VERSION 5.8 ;
BUSBITCHARS "[]" ;
DIVIDERCHAR "/" ;
UNITS
    DATABASE MICRONS 2000 ;
END UNITS

VIA PLL_RING_DCO_PHYS_via1_2_2240_1200_1_2_1040_1040
  VIARULE Via1_GEN_HH ;
  CUTSIZE 0.26 0.26 ;
  LAYERS Metal1 Via1 Metal2 ;
  CUTSPACING 0.26 0.26 ;
  ENCLOSURE 0.06 0.17 0.01 0.06 ;
  ROWCOL 1 2 ;
END PLL_RING_DCO_PHYS_via1_2_2240_1200_1_2_1040_1040

VIA PLL_RING_DCO_PHYS_via2_3_2240_1200_1_2_1040_1040
  VIARULE Via2_GEN_HH ;
  CUTSIZE 0.26 0.26 ;
  LAYERS Metal2 Via2 Metal3 ;
  CUTSPACING 0.26 0.26 ;
  ENCLOSURE 0.01 0.06 0.06 0.01 ;
  ROWCOL 1 2 ;
END PLL_RING_DCO_PHYS_via2_3_2240_1200_1_2_1040_1040

VIA PLL_RING_DCO_PHYS_via3_4_2240_1200_1_2_1040_1040
  VIARULE Via3_GEN_HH ;
  CUTSIZE 0.26 0.26 ;
  LAYERS Metal3 Via3 Metal4 ;
  CUTSPACING 0.26 0.26 ;
  ENCLOSURE 0.06 0.01 0.17 0.06 ;
  ROWCOL 1 2 ;
END PLL_RING_DCO_PHYS_via3_4_2240_1200_1_2_1040_1040

VIA PLL_RING_DCO_PHYS_via4_5_2240_1800_2_2_1040_1040
  VIARULE Via4_GEN_HH ;
  CUTSIZE 0.26 0.26 ;
  LAYERS Metal4 Via4 Metal5 ;
  CUTSPACING 0.26 0.26 ;
  ENCLOSURE 0.17 0.06 0.06 0.06 ;
  ROWCOL 2 2 ;
END PLL_RING_DCO_PHYS_via4_5_2240_1800_2_2_1040_1040

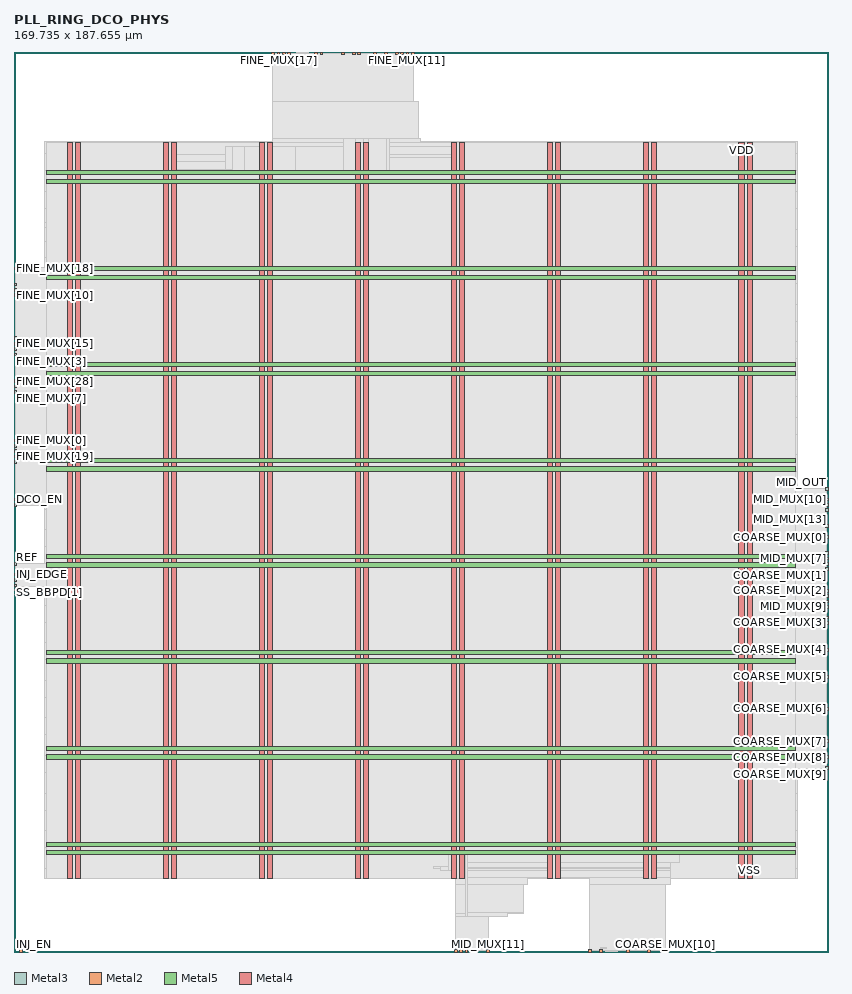
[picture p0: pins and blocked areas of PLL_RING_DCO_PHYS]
MACRO PLL_RING_DCO_PHYS
  FOREIGN PLL_RING_DCO_PHYS 0 0 ;
  CLASS BLOCK ;
  SIZE 169.735 BY 187.655 ;
  PIN COARSE_MUX[0]
    DIRECTION INPUT ;
    USE SIGNAL ;
    PORT
      LAYER Metal3 ;
        RECT  169.175 86.24 169.735 86.8 ;
    END
  END COARSE_MUX[0]
  PIN COARSE_MUX[10]
    DIRECTION INPUT ;
    USE SIGNAL ;
    PORT
      LAYER Metal2 ;
        RECT  135.52 0 136.08 0.56 ;
    END
  END COARSE_MUX[10]
  PIN COARSE_MUX[11]
    DIRECTION INPUT ;
    USE SIGNAL ;
    PORT
      LAYER Metal2 ;
        RECT  132.16 0 132.72 0.56 ;
    END
  END COARSE_MUX[11]
  PIN COARSE_MUX[12]
    DIRECTION INPUT ;
    USE SIGNAL ;
    PORT
      LAYER Metal2 ;
        RECT  127.68 0 128.24 0.56 ;
    END
  END COARSE_MUX[12]
  PIN COARSE_MUX[13]
    DIRECTION INPUT ;
    USE SIGNAL ;
    PORT
      LAYER Metal2 ;
        RECT  122.08 0 122.64 0.56 ;
    END
  END COARSE_MUX[13]
  PIN COARSE_MUX[14]
    DIRECTION INPUT ;
    USE SIGNAL ;
    PORT
      LAYER Metal2 ;
        RECT  119.84 0 120.4 0.56 ;
    END
  END COARSE_MUX[14]
  PIN COARSE_MUX[1]
    DIRECTION INPUT ;
    USE SIGNAL ;
    PORT
      LAYER Metal3 ;
        RECT  169.175 79.52 169.735 80.08 ;
    END
  END COARSE_MUX[1]
  PIN COARSE_MUX[2]
    DIRECTION INPUT ;
    USE SIGNAL ;
    PORT
      LAYER Metal3 ;
        RECT  169.175 75.04 169.735 75.6 ;
    END
  END COARSE_MUX[2]
  PIN COARSE_MUX[3]
    DIRECTION INPUT ;
    USE SIGNAL ;
    PORT
      LAYER Metal3 ;
        RECT  169.175 68.32 169.735 68.88 ;
    END
  END COARSE_MUX[3]
  PIN COARSE_MUX[4]
    DIRECTION INPUT ;
    USE SIGNAL ;
    PORT
      LAYER Metal3 ;
        RECT  169.175 62.72 169.735 63.28 ;
    END
  END COARSE_MUX[4]
  PIN COARSE_MUX[5]
    DIRECTION INPUT ;
    USE SIGNAL ;
    PORT
      LAYER Metal3 ;
        RECT  169.175 57.12 169.735 57.68 ;
    END
  END COARSE_MUX[5]
  PIN COARSE_MUX[6]
    DIRECTION INPUT ;
    USE SIGNAL ;
    PORT
      LAYER Metal3 ;
        RECT  169.175 50.4 169.735 50.96 ;
    END
  END COARSE_MUX[6]
  PIN COARSE_MUX[7]
    DIRECTION INPUT ;
    USE SIGNAL ;
    PORT
      LAYER Metal3 ;
        RECT  169.175 43.68 169.735 44.24 ;
    END
  END COARSE_MUX[7]
  PIN COARSE_MUX[8]
    DIRECTION INPUT ;
    USE SIGNAL ;
    PORT
      LAYER Metal3 ;
        RECT  169.175 40.32 169.735 40.88 ;
    END
  END COARSE_MUX[8]
  PIN COARSE_MUX[9]
    DIRECTION INPUT ;
    USE SIGNAL ;
    PORT
      LAYER Metal3 ;
        RECT  169.175 38.08 169.735 38.64 ;
    END
  END COARSE_MUX[9]
  PIN DCO_EN
    DIRECTION INPUT ;
    USE SIGNAL ;
    PORT
      LAYER Metal3 ;
        RECT  0 94.08 0.56 94.64 ;
    END
  END DCO_EN
  PIN FINE_MUX[0]
    DIRECTION INPUT ;
    USE SIGNAL ;
    PORT
      LAYER Metal3 ;
        RECT  0 106.4 0.56 106.96 ;
    END
  END FINE_MUX[0]
  PIN FINE_MUX[10]
    DIRECTION INPUT ;
    USE SIGNAL ;
    PORT
      LAYER Metal3 ;
        RECT  0 136.64 0.56 137.2 ;
    END
  END FINE_MUX[10]
  PIN FINE_MUX[11]
    DIRECTION INPUT ;
    USE SIGNAL ;
    PORT
      LAYER Metal2 ;
        RECT  81.76 187.095 82.32 187.655 ;
    END
  END FINE_MUX[11]
  PIN FINE_MUX[12]
    DIRECTION INPUT ;
    USE SIGNAL ;
    PORT
      LAYER Metal2 ;
        RECT  71.68 187.095 72.24 187.655 ;
    END
  END FINE_MUX[12]
  PIN FINE_MUX[13]
    DIRECTION INPUT ;
    USE SIGNAL ;
    PORT
      LAYER Metal2 ;
        RECT  68.32 187.095 68.88 187.655 ;
    END
  END FINE_MUX[13]
  PIN FINE_MUX[14]
    DIRECTION INPUT ;
    USE SIGNAL ;
    PORT
      LAYER Metal2 ;
        RECT  77.28 187.095 77.84 187.655 ;
    END
  END FINE_MUX[14]
  PIN FINE_MUX[15]
    DIRECTION INPUT ;
    USE SIGNAL ;
    PORT
      LAYER Metal3 ;
        RECT  0 126.56 0.56 127.12 ;
    END
  END FINE_MUX[15]
  PIN FINE_MUX[16]
    DIRECTION INPUT ;
    USE SIGNAL ;
    PORT
      LAYER Metal2 ;
        RECT  79.52 187.095 80.08 187.655 ;
    END
  END FINE_MUX[16]
  PIN FINE_MUX[17]
    DIRECTION INPUT ;
    USE SIGNAL ;
    PORT
      LAYER Metal2 ;
        RECT  54.88 187.095 55.44 187.655 ;
    END
  END FINE_MUX[17]
  PIN FINE_MUX[18]
    DIRECTION INPUT ;
    USE SIGNAL ;
    PORT
      LAYER Metal3 ;
        RECT  0 142.24 0.56 142.8 ;
    END
  END FINE_MUX[18]
  PIN FINE_MUX[19]
    DIRECTION INPUT ;
    USE SIGNAL ;
    PORT
      LAYER Metal3 ;
        RECT  0 103.04 0.56 103.6 ;
    END
  END FINE_MUX[19]
  PIN FINE_MUX[1]
    DIRECTION INPUT ;
    USE SIGNAL ;
    PORT
      LAYER Metal3 ;
        RECT  0 125.44 0.56 126 ;
    END
  END FINE_MUX[1]
  PIN FINE_MUX[20]
    DIRECTION INPUT ;
    USE SIGNAL ;
    PORT
      LAYER Metal3 ;
        RECT  0 138.88 0.56 139.44 ;
    END
  END FINE_MUX[20]
  PIN FINE_MUX[21]
    DIRECTION INPUT ;
    USE SIGNAL ;
    PORT
      LAYER Metal2 ;
        RECT  80.64 187.095 81.2 187.655 ;
    END
  END FINE_MUX[21]
  PIN FINE_MUX[22]
    DIRECTION INPUT ;
    USE SIGNAL ;
    PORT
      LAYER Metal3 ;
        RECT  0 104.16 0.56 104.72 ;
    END
  END FINE_MUX[22]
  PIN FINE_MUX[23]
    DIRECTION INPUT ;
    USE SIGNAL ;
    PORT
      LAYER Metal2 ;
        RECT  53.76 187.095 54.32 187.655 ;
    END
  END FINE_MUX[23]
  PIN FINE_MUX[24]
    DIRECTION INPUT ;
    USE SIGNAL ;
    PORT
      LAYER Metal3 ;
        RECT  0 137.76 0.56 138.32 ;
    END
  END FINE_MUX[24]
  PIN FINE_MUX[25]
    DIRECTION INPUT ;
    USE SIGNAL ;
    PORT
      LAYER Metal3 ;
        RECT  0 127.68 0.56 128.24 ;
    END
  END FINE_MUX[25]
  PIN FINE_MUX[26]
    DIRECTION INPUT ;
    USE SIGNAL ;
    PORT
      LAYER Metal3 ;
        RECT  0 105.28 0.56 105.84 ;
    END
  END FINE_MUX[26]
  PIN FINE_MUX[27]
    DIRECTION INPUT ;
    USE SIGNAL ;
    PORT
      LAYER Metal2 ;
        RECT  57.12 187.095 57.68 187.655 ;
    END
  END FINE_MUX[27]
  PIN FINE_MUX[28]
    DIRECTION INPUT ;
    USE SIGNAL ;
    PORT
      LAYER Metal3 ;
        RECT  0 118.72 0.56 119.28 ;
    END
  END FINE_MUX[28]
  PIN FINE_MUX[29]
    DIRECTION INPUT ;
    USE SIGNAL ;
    PORT
      LAYER Metal2 ;
        RECT  70.56 187.095 71.12 187.655 ;
    END
  END FINE_MUX[29]
  PIN FINE_MUX[2]
    DIRECTION INPUT ;
    USE SIGNAL ;
    PORT
      LAYER Metal2 ;
        RECT  75.04 187.095 75.6 187.655 ;
    END
  END FINE_MUX[2]
  PIN FINE_MUX[30]
    DIRECTION INPUT ;
    USE SIGNAL ;
    PORT
      LAYER Metal2 ;
        RECT  62.72 187.095 63.28 187.655 ;
    END
  END FINE_MUX[30]
  PIN FINE_MUX[3]
    DIRECTION INPUT ;
    USE SIGNAL ;
    PORT
      LAYER Metal3 ;
        RECT  0 124.32 0.56 124.88 ;
    END
  END FINE_MUX[3]
  PIN FINE_MUX[4]
    DIRECTION INPUT ;
    USE SIGNAL ;
    PORT
      LAYER Metal3 ;
        RECT  0 117.6 0.56 118.16 ;
    END
  END FINE_MUX[4]
  PIN FINE_MUX[5]
    DIRECTION INPUT ;
    USE SIGNAL ;
    PORT
      LAYER Metal2 ;
        RECT  82.88 187.095 83.44 187.655 ;
    END
  END FINE_MUX[5]
  PIN FINE_MUX[6]
    DIRECTION INPUT ;
    USE SIGNAL ;
    PORT
      LAYER Metal2 ;
        RECT  63.84 187.095 64.4 187.655 ;
    END
  END FINE_MUX[6]
  PIN FINE_MUX[7]
    DIRECTION INPUT ;
    USE SIGNAL ;
    PORT
      LAYER Metal3 ;
        RECT  0 116.48 0.56 117.04 ;
    END
  END FINE_MUX[7]
  PIN FINE_MUX[8]
    DIRECTION INPUT ;
    USE SIGNAL ;
    PORT
      LAYER Metal3 ;
        RECT  0 101.92 0.56 102.48 ;
    END
  END FINE_MUX[8]
  PIN FINE_MUX[9]
    DIRECTION INPUT ;
    USE SIGNAL ;
    PORT
      LAYER Metal2 ;
        RECT  56 187.095 56.56 187.655 ;
    END
  END FINE_MUX[9]
  PIN INJ_EDGE
    DIRECTION OUTPUT ;
    USE SIGNAL ;
    PORT
      LAYER Metal3 ;
        RECT  0 78.4 0.56 78.96 ;
    END
  END INJ_EDGE
  PIN INJ_EN
    DIRECTION INPUT ;
    USE SIGNAL ;
    PORT
      LAYER Metal2 ;
        RECT  1.12 0 1.68 0.56 ;
    END
  END INJ_EN
  PIN MID_MUX[0]
    DIRECTION INPUT ;
    USE SIGNAL ;
    PORT
      LAYER Metal3 ;
        RECT  169.175 72.8 169.735 73.36 ;
    END
  END MID_MUX[0]
  PIN MID_MUX[10]
    DIRECTION INPUT ;
    USE SIGNAL ;
    PORT
      LAYER Metal3 ;
        RECT  169.175 94.08 169.735 94.64 ;
    END
  END MID_MUX[10]
  PIN MID_MUX[11]
    DIRECTION INPUT ;
    USE SIGNAL ;
    PORT
      LAYER Metal2 ;
        RECT  98.56 0 99.12 0.56 ;
    END
  END MID_MUX[11]
  PIN MID_MUX[12]
    DIRECTION INPUT ;
    USE SIGNAL ;
    PORT
      LAYER Metal3 ;
        RECT  169.175 80.64 169.735 81.2 ;
    END
  END MID_MUX[12]
  PIN MID_MUX[13]
    DIRECTION INPUT ;
    USE SIGNAL ;
    PORT
      LAYER Metal3 ;
        RECT  169.175 88.48 169.735 89.04 ;
    END
  END MID_MUX[13]
  PIN MID_MUX[14]
    DIRECTION INPUT ;
    USE SIGNAL ;
    PORT
      LAYER Metal2 ;
        RECT  91.84 0 92.4 0.56 ;
    END
  END MID_MUX[14]
  PIN MID_MUX[1]
    DIRECTION INPUT ;
    USE SIGNAL ;
    PORT
      LAYER Metal3 ;
        RECT  169.175 82.88 169.735 83.44 ;
    END
  END MID_MUX[1]
  PIN MID_MUX[2]
    DIRECTION INPUT ;
    USE SIGNAL ;
    PORT
      LAYER Metal3 ;
        RECT  169.175 73.92 169.735 74.48 ;
    END
  END MID_MUX[2]
  PIN MID_MUX[3]
    DIRECTION INPUT ;
    USE SIGNAL ;
    PORT
      LAYER Metal3 ;
        RECT  169.175 69.44 169.735 70 ;
    END
  END MID_MUX[3]
  PIN MID_MUX[4]
    DIRECTION INPUT ;
    USE SIGNAL ;
    PORT
      LAYER Metal3 ;
        RECT  169.175 92.96 169.735 93.52 ;
    END
  END MID_MUX[4]
  PIN MID_MUX[5]
    DIRECTION INPUT ;
    USE SIGNAL ;
    PORT
      LAYER Metal3 ;
        RECT  169.175 91.84 169.735 92.4 ;
    END
  END MID_MUX[5]
  PIN MID_MUX[6]
    DIRECTION INPUT ;
    USE SIGNAL ;
    PORT
      LAYER Metal2 ;
        RECT  92.96 0 93.52 0.56 ;
    END
  END MID_MUX[6]
  PIN MID_MUX[7]
    DIRECTION INPUT ;
    USE SIGNAL ;
    PORT
      LAYER Metal3 ;
        RECT  169.175 81.76 169.735 82.32 ;
    END
  END MID_MUX[7]
  PIN MID_MUX[8]
    DIRECTION INPUT ;
    USE SIGNAL ;
    PORT
      LAYER Metal2 ;
        RECT  94.08 0 94.64 0.56 ;
    END
  END MID_MUX[8]
  PIN MID_MUX[9]
    DIRECTION INPUT ;
    USE SIGNAL ;
    PORT
      LAYER Metal3 ;
        RECT  169.175 71.68 169.735 72.24 ;
    END
  END MID_MUX[9]
  PIN MID_OUT
    DIRECTION OUTPUT ;
    USE SIGNAL ;
    PORT
      LAYER Metal3 ;
        RECT  169.175 96.32 169.735 96.88 ;
    END
  END MID_OUT
  PIN OUT
    DIRECTION OUTPUT ;
    USE SIGNAL ;
    PORT
      LAYER Metal3 ;
        RECT  0 92.96 0.56 93.52 ;
    END
  END OUT
  PIN REF
    DIRECTION INPUT ;
    USE SIGNAL ;
    PORT
      LAYER Metal3 ;
        RECT  0 80.64 0.56 81.2 ;
    END
  END REF
  PIN SS_BBPD[0]
    DIRECTION OUTPUT ;
    USE SIGNAL ;
    PORT
      LAYER Metal3 ;
        RECT  0 77.28 0.56 77.84 ;
    END
  END SS_BBPD[0]
  PIN SS_BBPD[1]
    DIRECTION OUTPUT ;
    USE SIGNAL ;
    PORT
      LAYER Metal3 ;
        RECT  0 76.16 0.56 76.72 ;
    END
  END SS_BBPD[1]
  PIN VDD
    DIRECTION INOUT ;
    USE POWER ;
    PORT
      LAYER Metal5 ;
        RECT  6.72 160.23 162.96 161.13 ;
        RECT  6.72 140.23 162.96 141.13 ;
        RECT  6.72 120.23 162.96 121.13 ;
        RECT  6.72 100.23 162.96 101.13 ;
        RECT  6.72 80.23 162.96 81.13 ;
        RECT  6.72 60.23 162.96 61.13 ;
        RECT  6.72 40.23 162.96 41.13 ;
        RECT  6.72 20.23 162.96 21.13 ;
      LAYER Metal4 ;
        RECT  151.16 15.38 152.28 168.86 ;
        RECT  131.16 15.38 132.28 168.86 ;
        RECT  111.16 15.38 112.28 168.86 ;
        RECT  91.16 15.38 92.28 168.86 ;
        RECT  71.16 15.38 72.28 168.86 ;
        RECT  51.16 15.38 52.28 168.86 ;
        RECT  31.16 15.38 32.28 168.86 ;
        RECT  11.16 15.38 12.28 168.86 ;
    END
  END VDD
  PIN VSS
    DIRECTION INOUT ;
    USE GROUND ;
    PORT
      LAYER Metal5 ;
        RECT  6.72 162.03 162.96 162.93 ;
        RECT  6.72 142.03 162.96 142.93 ;
        RECT  6.72 122.03 162.96 122.93 ;
        RECT  6.72 102.03 162.96 102.93 ;
        RECT  6.72 82.03 162.96 82.93 ;
        RECT  6.72 62.03 162.96 62.93 ;
        RECT  6.72 42.03 162.96 42.93 ;
        RECT  6.72 22.03 162.96 22.93 ;
      LAYER Metal4 ;
        RECT  152.84 15.38 153.96 168.86 ;
        RECT  132.84 15.38 133.96 168.86 ;
        RECT  112.84 15.38 113.96 168.86 ;
        RECT  92.84 15.38 93.96 168.86 ;
        RECT  72.84 15.38 73.96 168.86 ;
        RECT  52.84 15.38 53.96 168.86 ;
        RECT  32.84 15.38 33.96 168.86 ;
        RECT  12.84 15.38 13.96 168.86 ;
    END
  END VSS
  OBS
    LAYER Pwell ;
     RECT  6.29 15.25 163.39 17.45 ;
     RECT  6.29 21.75 163.39 25.29 ;
     RECT  6.29 29.59 163.39 33.13 ;
     RECT  6.29 37.43 163.39 40.97 ;
     RECT  6.29 45.27 163.39 48.81 ;
     RECT  6.29 53.11 163.39 56.65 ;
     RECT  6.29 60.95 163.39 64.49 ;
     RECT  6.29 68.79 163.39 72.33 ;
     RECT  6.29 76.63 163.39 80.17 ;
     RECT  6.29 84.47 163.39 88.01 ;
     RECT  6.29 92.31 163.39 95.85 ;
     RECT  6.29 100.15 163.39 103.69 ;
     RECT  6.29 107.99 163.39 111.53 ;
     RECT  6.29 115.83 163.39 119.37 ;
     RECT  6.29 123.67 163.39 127.21 ;
     RECT  6.29 131.51 163.39 135.05 ;
     RECT  6.29 139.35 163.39 142.89 ;
     RECT  6.29 147.19 163.39 150.73 ;
     RECT  6.29 155.03 163.39 158.57 ;
     RECT  6.29 162.87 163.39 166.41 ;
    LAYER Nwell ;
     RECT  6.29 17.45 163.39 21.75 ;
     RECT  6.29 25.29 163.39 29.59 ;
     RECT  6.29 33.13 163.39 37.43 ;
     RECT  6.29 40.97 163.39 45.27 ;
     RECT  6.29 48.81 163.39 53.11 ;
     RECT  6.29 56.65 163.39 60.95 ;
     RECT  6.29 64.49 163.39 68.79 ;
     RECT  6.29 72.33 163.39 76.63 ;
     RECT  6.29 80.17 163.39 84.47 ;
     RECT  6.29 88.01 163.39 92.31 ;
     RECT  6.29 95.85 163.39 100.15 ;
     RECT  6.29 103.69 163.39 107.99 ;
     RECT  6.29 111.53 163.39 115.83 ;
     RECT  6.29 119.37 163.39 123.67 ;
     RECT  6.29 127.21 163.39 131.51 ;
     RECT  6.29 135.05 163.39 139.35 ;
     RECT  6.29 142.89 163.39 147.19 ;
     RECT  6.29 150.73 163.39 155.03 ;
     RECT  6.29 158.57 163.39 162.87 ;
     RECT  6.29 166.41 163.39 168.99 ;
    LAYER Metal1 ;
     RECT  6.72 15.38 162.96 168.86 ;
    LAYER Metal2 ;
     RECT  123.34 0.14 125.86 0.28 ;
     RECT  91.98 0.28 98.98 7.42 ;
     RECT  91.98 7.42 102.9 7.98 ;
     RECT  91.98 7.98 106.26 14.14 ;
     RECT  119.98 0.28 135.94 14.14 ;
     RECT  91.98 14.14 107.1 15.49 ;
     RECT  119.98 14.14 136.78 15.49 ;
     RECT  91.98 15.49 136.78 16.94 ;
     RECT  88.9 16.94 136.78 17.31 ;
     RECT  87.5 17.31 136.78 17.64 ;
     RECT  90.58 17.64 136.78 18.62 ;
     RECT  13 15.49 13.8 19.41 ;
     RECT  33 15.49 33.8 19.41 ;
     RECT  53 15.49 53.8 19.41 ;
     RECT  73 15.49 73.8 19.41 ;
     RECT  153 15.49 153.8 19.41 ;
     RECT  90.58 18.62 138.74 20.58 ;
     RECT  151.32 19.41 153.8 20.58 ;
     RECT  90.58 20.58 153.8 21.7 ;
     RECT  91.32 21.7 153.8 26.18 ;
     RECT  91.32 26.18 153.86 29.26 ;
     RECT  91.32 29.26 157.78 29.54 ;
     RECT  149.66 29.54 157.78 29.82 ;
     RECT  149.66 29.82 160.58 30.1 ;
     RECT  151.32 30.1 160.58 33.46 ;
     RECT  151.32 33.46 161.42 35.98 ;
     RECT  151.32 35.98 162.26 38.22 ;
     RECT  31.32 19.41 33.8 45.22 ;
     RECT  151.32 38.22 162.82 45.78 ;
     RECT  28.98 45.22 33.8 46.06 ;
     RECT  91.32 29.54 113.8 46.06 ;
     RECT  28.98 46.06 34.58 47.74 ;
     RECT  28.7 47.74 34.58 48.86 ;
     RECT  51.32 19.41 53.8 48.86 ;
     RECT  151.32 45.78 161.42 48.86 ;
     RECT  28.7 48.86 53.8 49.14 ;
     RECT  91.32 46.06 114.66 49.14 ;
     RECT  28.7 49.14 60.06 49.98 ;
     RECT  71.32 19.41 73.8 49.98 ;
     RECT  11.32 19.41 13.8 51.47 ;
     RECT  28.7 49.98 73.8 51.47 ;
     RECT  91.32 49.14 118.86 51.66 ;
     RECT  131.32 29.54 133.8 51.66 ;
     RECT  149.66 48.86 161.42 51.94 ;
     RECT  146.3 51.94 161.42 52.78 ;
     RECT  11.32 51.47 73.8 53.06 ;
     RECT  91.32 51.66 133.8 55.58 ;
     RECT  145.74 52.78 161.42 55.58 ;
     RECT  28.42 53.06 73.8 56.7 ;
     RECT  91.32 55.58 161.42 56.7 ;
     RECT  28.42 56.7 161.42 59.5 ;
     RECT  11.32 53.06 13.8 67.52 ;
     RECT  28.42 59.5 162.26 67.52 ;
     RECT  11.32 67.52 162.26 68.6 ;
     RECT  11.32 68.6 118.02 69.02 ;
     RECT  10.78 69.02 118.02 71.82 ;
     RECT  9.1 71.82 118.02 72.52 ;
     RECT  9.1 72.52 114.1 72.66 ;
     RECT  129.5 68.6 162.26 72.94 ;
     RECT  129.5 72.94 164.5 73.22 ;
     RECT  130.62 73.22 164.5 73.78 ;
     RECT  131.32 73.78 164.5 76.58 ;
     RECT  9.1 72.66 113.8 84.98 ;
     RECT  131.32 76.58 162.82 84.98 ;
     RECT  9.1 84.98 53.8 88.34 ;
     RECT  66.22 84.98 113.8 88.34 ;
     RECT  8.26 88.34 53.8 88.9 ;
     RECT  8.26 88.9 35.14 90.86 ;
     RECT  7.42 90.86 35.14 91.14 ;
     RECT  90.3 88.34 113.8 91.14 ;
     RECT  66.22 88.34 77.7 92.12 ;
     RECT  131.32 84.98 162.26 92.26 ;
     RECT  131.32 92.26 161.42 94.78 ;
     RECT  130.62 94.78 161.42 95.06 ;
     RECT  131.32 95.06 161.42 95.9 ;
     RECT  131.32 95.9 160.58 98.98 ;
     RECT  150.5 98.98 160.02 100.1 ;
     RECT  68.46 92.12 77.7 100.66 ;
     RECT  70.7 100.66 77.7 102.9 ;
     RECT  71.32 102.9 77.7 103.74 ;
     RECT  91.32 91.14 113.8 103.74 ;
     RECT  151.32 100.1 160.02 104.02 ;
     RECT  7.42 91.14 33.8 104.3 ;
     RECT  151.32 104.02 156.1 104.58 ;
     RECT  71.32 103.74 113.8 107.1 ;
     RECT  71.32 107.1 115.78 107.94 ;
     RECT  6.86 104.3 33.8 112.42 ;
     RECT  71.32 107.94 118.3 112.42 ;
     RECT  91.32 112.42 118.3 115.5 ;
     RECT  91.32 115.5 119.98 116.62 ;
     RECT  131.32 98.98 137.9 116.62 ;
     RECT  91.32 116.62 137.9 119.23 ;
     RECT  8.26 112.42 33.8 124.46 ;
     RECT  7.42 124.46 33.8 127.82 ;
     RECT  91.32 119.23 139.3 130.2 ;
     RECT  111.32 130.2 139.3 130.62 ;
     RECT  151.32 104.58 153.8 130.62 ;
     RECT  91.32 130.2 99.82 131.18 ;
     RECT  91.32 131.18 97.86 132.3 ;
     RECT  90.3 132.3 97.86 134.91 ;
     RECT  71.32 112.42 77.7 136.22 ;
     RECT  90.02 134.91 97.86 136.22 ;
     RECT  6.86 127.82 33.8 142.38 ;
     RECT  71.32 136.22 97.86 142.94 ;
     RECT  111.32 130.62 153.8 142.94 ;
     RECT  71.32 142.94 153.8 143.22 ;
     RECT  71.32 143.22 113.8 144.06 ;
     RECT  126.7 143.22 153.8 144.34 ;
     RECT  6.3 142.38 33.8 144.9 ;
     RECT  70.14 144.06 113.8 146.86 ;
     RECT  126.98 144.34 153.8 146.86 ;
     RECT  69.02 146.86 113.8 147.7 ;
     RECT  131.32 146.86 153.8 147.7 ;
     RECT  6.3 144.9 18.62 148.12 ;
     RECT  6.3 148.12 14.98 151.06 ;
     RECT  6.3 151.06 13.8 152.18 ;
     RECT  8.26 152.18 13.8 154.7 ;
     RECT  51.32 88.9 53.8 154.7 ;
     RECT  69.02 147.7 93.8 154.7 ;
     RECT  48.02 154.7 93.8 161.23 ;
     RECT  48.02 161.23 94.22 161.56 ;
     RECT  48.02 161.56 93.8 162.35 ;
     RECT  31.32 144.9 33.8 162.54 ;
     RECT  45.5 162.35 93.8 162.54 ;
     RECT  11.32 154.7 13.8 164.83 ;
     RECT  31.32 162.54 93.8 164.83 ;
     RECT  111.32 147.7 113.8 164.83 ;
     RECT  131.32 147.7 133.8 164.83 ;
     RECT  151.32 147.7 153.8 164.83 ;
     RECT  31.32 164.83 92.12 166.18 ;
     RECT  44.1 166.18 92.12 167.86 ;
     RECT  11.32 164.83 12.12 168.75 ;
     RECT  31.32 166.18 32.12 168.75 ;
     RECT  51.32 167.86 92.12 168.75 ;
     RECT  111.32 164.83 112.12 168.75 ;
     RECT  131.32 164.83 132.12 168.75 ;
     RECT  151.32 164.83 152.12 168.75 ;
     RECT  53.9 168.75 84.7 169.54 ;
     RECT  53.9 169.54 84.42 177.38 ;
     RECT  53.9 177.38 83.3 187.32 ;
     RECT  58.94 187.32 61.46 187.46 ;
    LAYER Metal3 ;
     RECT  0.28 76.3 11.27 81.06 ;
     RECT  0.28 93.1 11.27 142.66 ;
     RECT  11.27 19.46 12.17 168.7 ;
     RECT  12.17 19.46 12.95 164.78 ;
     RECT  12.95 15.54 13.85 164.78 ;
     RECT  13.85 75.74 18.62 148.26 ;
     RECT  13.85 51.66 31.27 51.94 ;
     RECT  18.62 75.74 31.27 144.9 ;
     RECT  31.27 19.46 32.17 168.7 ;
     RECT  32.17 19.46 32.95 164.78 ;
     RECT  32.95 15.54 33.85 164.78 ;
     RECT  33.85 48.86 34.3 51.94 ;
     RECT  33.85 86.94 37.38 96.18 ;
     RECT  33.85 163.1 44.1 164.78 ;
     RECT  44.1 163.1 45.5 167.86 ;
     RECT  45.5 162.54 48.02 167.86 ;
     RECT  34.3 51.66 48.3 51.94 ;
     RECT  48.3 51.66 51.27 54.18 ;
     RECT  33.85 72.38 51.27 72.66 ;
     RECT  37.38 95.9 51.27 96.18 ;
     RECT  48.02 154.7 51.27 167.86 ;
     RECT  51.27 19.46 52.17 168.7 ;
     RECT  52.17 19.46 52.95 167.86 ;
     RECT  52.95 15.54 53.85 167.86 ;
     RECT  53.85 155.82 58.66 167.86 ;
     RECT  53.85 51.66 60.06 53.06 ;
     RECT  53.85 72.38 65.38 72.66 ;
     RECT  65.38 71.26 65.66 72.66 ;
     RECT  53.85 95.9 66.22 96.18 ;
     RECT  66.22 91.98 67.62 96.18 ;
     RECT  58.66 159.74 68.74 167.86 ;
     RECT  60.06 52.78 71.27 53.06 ;
     RECT  65.66 71.26 71.27 76.02 ;
     RECT  67.62 91.42 71.27 96.18 ;
     RECT  71.26 146.86 71.27 147.14 ;
     RECT  68.74 159.74 71.27 169.54 ;
     RECT  71.27 19.46 72.95 169.54 ;
     RECT  72.95 15.54 73.85 169.54 ;
     RECT  73.85 95.9 77.7 107.94 ;
     RECT  73.85 142.94 77.7 169.54 ;
     RECT  77.7 146.86 78.26 169.54 ;
     RECT  87.5 17.5 88.9 17.78 ;
     RECT  88.9 16.94 90.58 17.78 ;
     RECT  90.58 16.94 91.27 21.7 ;
     RECT  73.85 59.5 91.27 59.78 ;
     RECT  73.85 84.14 91.27 84.42 ;
     RECT  77.7 99.82 91.27 107.94 ;
     RECT  90.02 135.1 91.27 135.38 ;
     RECT  78.26 146.86 91.27 165.62 ;
     RECT  91.27 16.94 92.17 168.7 ;
     RECT  92.17 16.94 92.95 164.78 ;
     RECT  92.95 15.54 93.85 164.78 ;
     RECT  93.85 15.54 94.22 29.54 ;
     RECT  93.85 161.42 94.22 161.7 ;
     RECT  94.22 7.42 94.5 29.54 ;
     RECT  94.5 21.42 96.18 29.54 ;
     RECT  96.18 22.54 98.42 29.54 ;
     RECT  94.5 7.42 102.9 8.26 ;
     RECT  102.9 7.98 106.26 8.26 ;
     RECT  93.85 50.54 107.1 50.82 ;
     RECT  93.85 72.38 107.94 72.66 ;
     RECT  98.42 22.54 111.27 25.62 ;
     RECT  107.1 48.86 111.27 50.82 ;
     RECT  107.94 71.26 111.27 72.66 ;
     RECT  93.85 88.06 111.27 109.62 ;
     RECT  93.85 130.06 111.27 130.34 ;
     RECT  93.85 144.06 111.27 144.34 ;
     RECT  111.27 15.54 112.17 168.7 ;
     RECT  112.17 15.54 113.85 164.78 ;
     RECT  113.85 52.78 118.02 72.66 ;
     RECT  118.02 52.78 118.3 68.74 ;
     RECT  118.3 52.78 119.42 53.06 ;
     RECT  118.3 68.46 119.7 68.74 ;
     RECT  122.22 0.7 123.62 0.98 ;
     RECT  129.5 72.94 130.62 73.22 ;
     RECT  130.62 72.94 131.18 73.78 ;
     RECT  113.85 21.42 131.27 29.54 ;
     RECT  131.18 68.46 131.27 73.78 ;
     RECT  113.85 88.62 131.27 88.9 ;
     RECT  113.85 100.38 131.27 100.66 ;
     RECT  125.58 142.94 131.27 143.22 ;
     RECT  131.27 19.46 132.17 168.7 ;
     RECT  132.17 19.46 132.95 164.78 ;
     RECT  132.95 15.54 133.85 164.78 ;
     RECT  133.85 55.58 135.66 123.62 ;
     RECT  135.66 55.58 136.5 104.02 ;
     RECT  133.85 139.02 137.9 143.22 ;
     RECT  135.66 119.42 139.3 123.62 ;
     RECT  136.5 55.58 146.86 100.66 ;
     RECT  133.85 21.42 149.66 29.54 ;
     RECT  146.86 52.22 150.78 100.66 ;
     RECT  149.66 21.42 151.27 30.1 ;
     RECT  150.78 48.86 151.27 100.66 ;
     RECT  137.9 139.02 151.27 139.3 ;
     RECT  151.27 19.46 152.17 168.7 ;
     RECT  152.17 19.46 152.95 164.78 ;
     RECT  152.95 15.54 153.85 164.78 ;
     RECT  153.85 29.26 157.78 102.9 ;
     RECT  157.78 29.82 159.18 102.9 ;
     RECT  159.18 29.82 160.02 98.42 ;
     RECT  160.02 29.82 160.58 96.74 ;
     RECT  160.58 38.22 169.4 96.74 ;
    LAYER Metal4 ;
     RECT  151.16 15.38 153.96 79.1 ;
     RECT  149.66 79.1 153.96 84.98 ;
     RECT  11.16 15.38 13.96 104.86 ;
     RECT  9.66 104.86 13.96 112.98 ;
     RECT  11.16 112.98 13.96 168.86 ;
     RECT  31.16 15.38 33.96 168.86 ;
     RECT  51.16 15.38 53.96 168.86 ;
     RECT  71.16 15.38 73.96 168.86 ;
     RECT  91.16 15.38 93.96 168.86 ;
     RECT  111.16 15.38 113.96 168.86 ;
     RECT  131.16 15.38 133.96 168.86 ;
     RECT  151.16 84.98 153.96 168.86 ;
    LAYER Metal5 ;
     RECT  6.72 20.23 162.96 162.93 ;
  END
END PLL_RING_DCO_PHYS
END LIBRARY
